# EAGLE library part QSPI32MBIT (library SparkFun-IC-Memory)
Integrated Silicon Solution Inc. IS25LP032D The IS25LP032D Serial Flash memory offers a versatile storage solution with high flexibility and performance in a simplified pin count package. ISSI’s “Industry Standard Serial Interface” Flash is for systems that require limited space, a low pin count, and low power consumption. The device is accessed through a 4-wire SPI Interface consisting of a Serial Data Input (SI), Serial Data Output (SO), Serial Clock (SCK), and Chip Enable (CE#) pins, which can also be configured to serve as multi-I/O (see pin descriptions). Datasheet

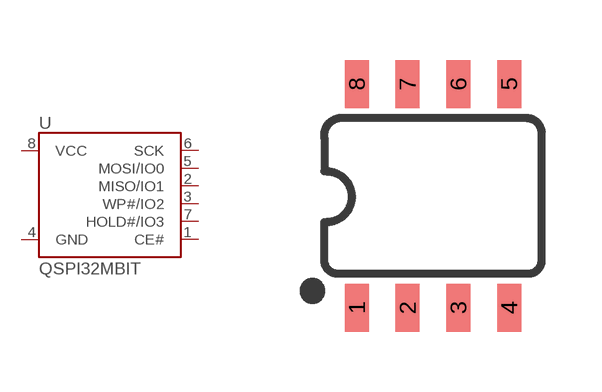
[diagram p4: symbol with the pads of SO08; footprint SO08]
Designator prefix U

## QSPI32MBIT (PROD_ID: IC-14501; VALUE: 32MBit)  [SO08]
1  CE#
2  MISO/IO1
3  WP#/IO2
4  GND
5  MOSI/IO0
6  SCK
7  HOLD#/IO3
8  VCC

## Footprint SO08 (pad centres in mm)
SOIC, 0.15 inch width
smd 0.6 x 1.2: 1 -1.905,-2.8; 2 -0.635,-2.8; 3 0.635,-2.8; 4 1.905,-2.8; 5 1.905,2.8; 6 0.635,2.8; 7 -0.635,2.8; 8 -1.905,2.8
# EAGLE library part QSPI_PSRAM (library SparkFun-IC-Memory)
QSPI PSRAM Quad-SPI PSRAM chips provide additional memory and are often highly standardized Example Parts LY68L6400SLIT

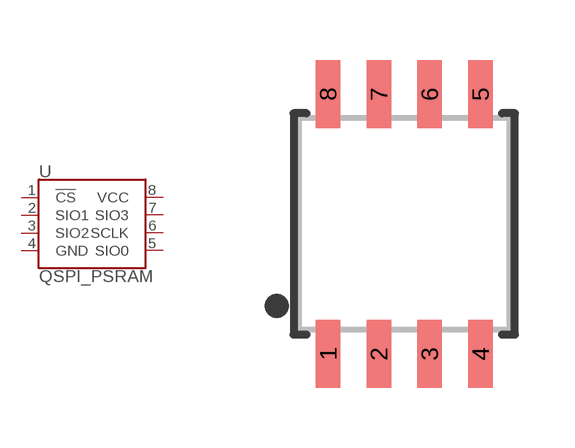
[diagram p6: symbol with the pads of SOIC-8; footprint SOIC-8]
Designator prefix U

## QSPI_PSRAM  [SOIC-8]
1  !CS
2  SIO1
3  SIO2
4  GND
5  SIO0
6  SCLK
7  SIO3
8  VCC

## Footprint SOIC-8 (pad centres in mm)
8-Pin SOIC 208-mil
smd 0.61 x 1.702: 1 -1.905,-3.251; 2 -0.635,-3.251; 3 0.635,-3.251; 4 1.905,-3.251; 5 1.905,3.251; 6 0.635,3.251; 7 -0.635,3.251; 8 -1.905,3.251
